VERSION 5.7 ;
  NOWIREEXTENSIONATPIN ON ;
  DIVIDERCHAR "/" ;
  BUSBITCHARS "[]" ;
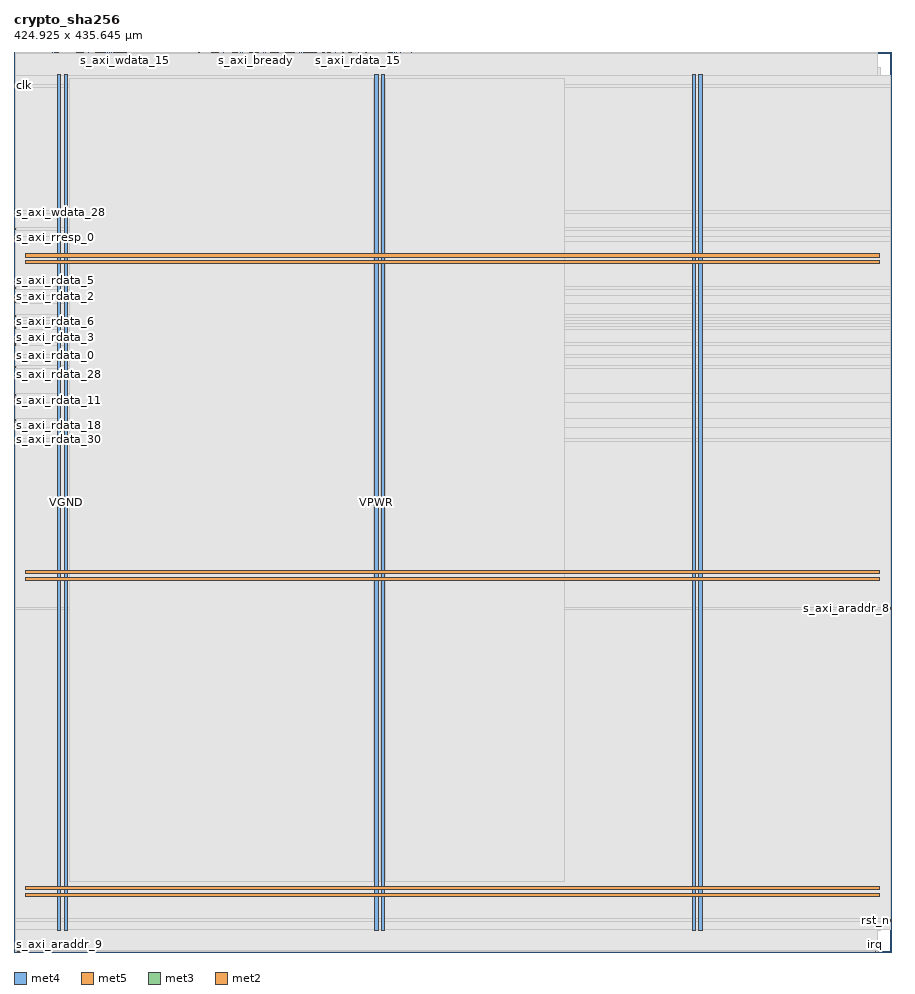
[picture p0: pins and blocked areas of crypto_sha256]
MACRO crypto_sha256
  CLASS BLOCK ;
  FOREIGN crypto_sha256 ;
  ORIGIN 0.000 0.000 ;
  SIZE 424.925 BY 435.645 ;
  PIN VGND
    DIRECTION INOUT ;
    USE GROUND ;
    PORT
      LAYER met4 ;
        RECT 24.340 10.640 25.940 424.560 ;
    END
    PORT
      LAYER met4 ;
        RECT 177.940 10.640 179.540 424.560 ;
    END
    PORT
      LAYER met4 ;
        RECT 331.540 10.640 333.140 424.560 ;
    END
    PORT
      LAYER met5 ;
        RECT 5.520 30.030 419.060 31.630 ;
    END
    PORT
      LAYER met5 ;
        RECT 5.520 183.210 419.060 184.810 ;
    END
    PORT
      LAYER met5 ;
        RECT 5.520 336.390 419.060 337.990 ;
    END
  END VGND
  PIN VPWR
    DIRECTION INOUT ;
    USE POWER ;
    PORT
      LAYER met4 ;
        RECT 21.040 10.640 22.640 424.560 ;
    END
    PORT
      LAYER met4 ;
        RECT 174.640 10.640 176.240 424.560 ;
    END
    PORT
      LAYER met4 ;
        RECT 328.240 10.640 329.840 424.560 ;
    END
    PORT
      LAYER met5 ;
        RECT 5.520 26.730 419.060 28.330 ;
    END
    PORT
      LAYER met5 ;
        RECT 5.520 179.910 419.060 181.510 ;
    END
    PORT
      LAYER met5 ;
        RECT 5.520 333.090 419.060 334.690 ;
    END
  END VPWR
  PIN clk
    DIRECTION INPUT ;
    USE SIGNAL ;
    ANTENNAGATEAREA 1.286700 ;
    ANTENNADIFFAREA 0.434700 ;
    PORT
      LAYER met3 ;
        RECT 0.000 418.920 0.600 419.520 ;
    END
  END clk
  PIN irq
    DIRECTION OUTPUT ;
    USE SIGNAL ;
    ANTENNAGATEAREA 0.434700 ;
    ANTENNADIFFAREA 1.137600 ;
    PORT
      LAYER met2 ;
        RECT 416.850 0.000 417.130 0.280 ;
    END
  END irq
  PIN rst_n
    DIRECTION INPUT ;
    USE SIGNAL ;
    ANTENNAGATEAREA 0.647700 ;
    ANTENNADIFFAREA 0.434700 ;
    PORT
      LAYER met3 ;
        RECT 424.325 15.000 424.925 15.600 ;
    END
  END rst_n
  PIN s_axi_araddr_0
    DIRECTION INPUT ;
    USE SIGNAL ;
    PORT
      LAYER met2 ;
        RECT 1.930 0.000 2.210 0.280 ;
    END
  END s_axi_araddr_0
  PIN s_axi_araddr_1
    DIRECTION INPUT ;
    USE SIGNAL ;
    PORT
      LAYER met2 ;
        RECT 2.850 0.000 3.130 0.280 ;
    END
  END s_axi_araddr_1
  PIN s_axi_araddr_10
    DIRECTION INPUT ;
    USE SIGNAL ;
    PORT
      LAYER met2 ;
        RECT 3.770 0.000 4.050 0.280 ;
    END
  END s_axi_araddr_10
  PIN s_axi_araddr_11
    DIRECTION INPUT ;
    USE SIGNAL ;
    ANTENNAGATEAREA 0.647700 ;
    ANTENNADIFFAREA 0.434700 ;
    PORT
      LAYER met2 ;
        RECT 192.370 435.365 192.650 435.645 ;
    END
  END s_axi_araddr_11
  PIN s_axi_araddr_2
    DIRECTION INPUT ;
    USE SIGNAL ;
    ANTENNAGATEAREA 0.647700 ;
    ANTENNADIFFAREA 0.434700 ;
    PORT
      LAYER met2 ;
        RECT 181.330 435.365 181.610 435.645 ;
    END
  END s_axi_araddr_2
  PIN s_axi_araddr_3
    DIRECTION INPUT ;
    USE SIGNAL ;
    ANTENNAGATEAREA 0.647700 ;
    ANTENNADIFFAREA 0.434700 ;
    PORT
      LAYER met2 ;
        RECT 185.010 435.365 185.290 435.645 ;
    END
  END s_axi_araddr_3
  PIN s_axi_araddr_4
    DIRECTION INPUT ;
    USE SIGNAL ;
    ANTENNAGATEAREA 0.647700 ;
    ANTENNADIFFAREA 0.434700 ;
    PORT
      LAYER met2 ;
        RECT 184.090 435.365 184.370 435.645 ;
    END
  END s_axi_araddr_4
  PIN s_axi_araddr_5
    DIRECTION INPUT ;
    USE SIGNAL ;
    ANTENNAGATEAREA 0.647700 ;
    ANTENNADIFFAREA 0.434700 ;
    PORT
      LAYER met2 ;
        RECT 183.170 435.365 183.450 435.645 ;
    END
  END s_axi_araddr_5
  PIN s_axi_araddr_6
    DIRECTION INPUT ;
    USE SIGNAL ;
    ANTENNAGATEAREA 0.647700 ;
    ANTENNADIFFAREA 0.434700 ;
    PORT
      LAYER met2 ;
        RECT 182.250 435.365 182.530 435.645 ;
    END
  END s_axi_araddr_6
  PIN s_axi_araddr_7
    DIRECTION INPUT ;
    USE SIGNAL ;
    ANTENNAGATEAREA 0.647700 ;
    ANTENNADIFFAREA 0.434700 ;
    PORT
      LAYER met2 ;
        RECT 186.850 435.365 187.130 435.645 ;
    END
  END s_axi_araddr_7
  PIN s_axi_araddr_8
    DIRECTION INPUT ;
    USE SIGNAL ;
    ANTENNAGATEAREA 0.631200 ;
    ANTENNADIFFAREA 0.434700 ;
    PORT
      LAYER met3 ;
        RECT 424.325 165.960 424.925 166.560 ;
    END
  END s_axi_araddr_8
  PIN s_axi_araddr_9
    DIRECTION INPUT ;
    USE SIGNAL ;
    PORT
      LAYER met2 ;
        RECT 4.690 0.000 4.970 0.280 ;
    END
  END s_axi_araddr_9
  PIN s_axi_arready
    DIRECTION OUTPUT ;
    USE SIGNAL ;
    ANTENNAGATEAREA 0.434700 ;
    ANTENNADIFFAREA 1.137600 ;
    PORT
      LAYER met2 ;
        RECT 127.970 435.365 128.250 435.645 ;
    END
  END s_axi_arready
  PIN s_axi_arvalid
    DIRECTION INPUT ;
    USE SIGNAL ;
    ANTENNAGATEAREA 0.647700 ;
    ANTENNADIFFAREA 0.434700 ;
    PORT
      LAYER met2 ;
        RECT 127.050 435.365 127.330 435.645 ;
    END
  END s_axi_arvalid
  PIN s_axi_awaddr_0
    DIRECTION INPUT ;
    USE SIGNAL ;
    ANTENNAGATEAREA 0.647700 ;
    ANTENNADIFFAREA 0.434700 ;
    PORT
      LAYER met2 ;
        RECT 132.570 435.365 132.850 435.645 ;
    END
  END s_axi_awaddr_0
  PIN s_axi_awaddr_1
    DIRECTION INPUT ;
    USE SIGNAL ;
    ANTENNAGATEAREA 0.647700 ;
    ANTENNADIFFAREA 0.434700 ;
    PORT
      LAYER met2 ;
        RECT 146.370 435.365 146.650 435.645 ;
    END
  END s_axi_awaddr_1
  PIN s_axi_awaddr_10
    DIRECTION INPUT ;
    USE SIGNAL ;
    ANTENNAGATEAREA 0.647700 ;
    ANTENNADIFFAREA 0.434700 ;
    PORT
      LAYER met2 ;
        RECT 141.770 435.365 142.050 435.645 ;
    END
  END s_axi_awaddr_10
  PIN s_axi_awaddr_11
    DIRECTION INPUT ;
    USE SIGNAL ;
    ANTENNAGATEAREA 0.647700 ;
    ANTENNADIFFAREA 0.434700 ;
    PORT
      LAYER met2 ;
        RECT 134.410 435.365 134.690 435.645 ;
    END
  END s_axi_awaddr_11
  PIN s_axi_awaddr_2
    DIRECTION INPUT ;
    USE SIGNAL ;
    ANTENNAGATEAREA 0.647700 ;
    ANTENNADIFFAREA 0.434700 ;
    PORT
      LAYER met2 ;
        RECT 115.090 435.365 115.370 435.645 ;
    END
  END s_axi_awaddr_2
  PIN s_axi_awaddr_3
    DIRECTION INPUT ;
    USE SIGNAL ;
    ANTENNAGATEAREA 0.647700 ;
    ANTENNADIFFAREA 0.434700 ;
    PORT
      LAYER met2 ;
        RECT 124.290 435.365 124.570 435.645 ;
    END
  END s_axi_awaddr_3
  PIN s_axi_awaddr_4
    DIRECTION INPUT ;
    USE SIGNAL ;
    ANTENNAGATEAREA 0.647700 ;
    ANTENNADIFFAREA 0.434700 ;
    PORT
      LAYER met2 ;
        RECT 139.930 435.365 140.210 435.645 ;
    END
  END s_axi_awaddr_4
  PIN s_axi_awaddr_5
    DIRECTION INPUT ;
    USE SIGNAL ;
    ANTENNAGATEAREA 0.647700 ;
    ANTENNADIFFAREA 0.434700 ;
    PORT
      LAYER met2 ;
        RECT 145.450 435.365 145.730 435.645 ;
    END
  END s_axi_awaddr_5
  PIN s_axi_awaddr_6
    DIRECTION INPUT ;
    USE SIGNAL ;
    ANTENNAGATEAREA 0.647700 ;
    ANTENNADIFFAREA 0.434700 ;
    PORT
      LAYER met2 ;
        RECT 144.530 435.365 144.810 435.645 ;
    END
  END s_axi_awaddr_6
  PIN s_axi_awaddr_7
    DIRECTION INPUT ;
    USE SIGNAL ;
    ANTENNAGATEAREA 0.647700 ;
    ANTENNADIFFAREA 0.434700 ;
    PORT
      LAYER met2 ;
        RECT 117.850 435.365 118.130 435.645 ;
    END
  END s_axi_awaddr_7
  PIN s_axi_awaddr_8
    DIRECTION INPUT ;
    USE SIGNAL ;
    ANTENNAGATEAREA 0.647700 ;
    ANTENNADIFFAREA 0.434700 ;
    PORT
      LAYER met2 ;
        RECT 135.330 435.365 135.610 435.645 ;
    END
  END s_axi_awaddr_8
  PIN s_axi_awaddr_9
    DIRECTION INPUT ;
    USE SIGNAL ;
    ANTENNAGATEAREA 0.647700 ;
    ANTENNADIFFAREA 0.434700 ;
    PORT
      LAYER met2 ;
        RECT 126.130 435.365 126.410 435.645 ;
    END
  END s_axi_awaddr_9
  PIN s_axi_awready
    DIRECTION OUTPUT ;
    USE SIGNAL ;
    ANTENNAGATEAREA 0.434700 ;
    ANTENNADIFFAREA 1.137600 ;
    PORT
      LAYER met2 ;
        RECT 125.210 435.365 125.490 435.645 ;
    END
  END s_axi_awready
  PIN s_axi_awvalid
    DIRECTION INPUT ;
    USE SIGNAL ;
    ANTENNAGATEAREA 0.647700 ;
    ANTENNADIFFAREA 0.434700 ;
    PORT
      LAYER met2 ;
        RECT 121.530 435.365 121.810 435.645 ;
    END
  END s_axi_awvalid
  PIN s_axi_bready
    DIRECTION INPUT ;
    USE SIGNAL ;
    ANTENNAGATEAREA 0.647700 ;
    ANTENNADIFFAREA 0.434700 ;
    PORT
      LAYER met2 ;
        RECT 116.930 435.365 117.210 435.645 ;
    END
  END s_axi_bready
  PIN s_axi_bresp_0
    DIRECTION OUTPUT ;
    USE SIGNAL ;
    ANTENNAGATEAREA 0.434700 ;
    ANTENNADIFFAREA 1.137600 ;
    PORT
      LAYER met2 ;
        RECT 110.490 435.365 110.770 435.645 ;
    END
  END s_axi_bresp_0
  PIN s_axi_bresp_1
    DIRECTION OUTPUT ;
    USE SIGNAL ;
    ANTENNAGATEAREA 0.434700 ;
    ANTENNADIFFAREA 1.137600 ;
    PORT
      LAYER met2 ;
        RECT 109.570 435.365 109.850 435.645 ;
    END
  END s_axi_bresp_1
  PIN s_axi_bvalid
    DIRECTION OUTPUT ;
    USE SIGNAL ;
    ANTENNAGATEAREA 0.434700 ;
    ANTENNADIFFAREA 1.137600 ;
    PORT
      LAYER met2 ;
        RECT 120.610 435.365 120.890 435.645 ;
    END
  END s_axi_bvalid
  PIN s_axi_rdata_0
    DIRECTION OUTPUT ;
    USE SIGNAL ;
    ANTENNAGATEAREA 0.434700 ;
    ANTENNADIFFAREA 1.137600 ;
    PORT
      LAYER met3 ;
        RECT 0.000 288.360 0.600 288.960 ;
    END
  END s_axi_rdata_0
  PIN s_axi_rdata_1
    DIRECTION OUTPUT ;
    USE SIGNAL ;
    ANTENNAGATEAREA 0.434700 ;
    ANTENNADIFFAREA 1.137600 ;
    PORT
      LAYER met3 ;
        RECT 0.000 301.960 0.600 302.560 ;
    END
  END s_axi_rdata_1
  PIN s_axi_rdata_10
    DIRECTION OUTPUT ;
    USE SIGNAL ;
    ANTENNAGATEAREA 0.434700 ;
    ANTENNADIFFAREA 1.137600 ;
    PORT
      LAYER met2 ;
        RECT 131.650 435.365 131.930 435.645 ;
    END
  END s_axi_rdata_10
  PIN s_axi_rdata_11
    DIRECTION OUTPUT ;
    USE SIGNAL ;
    ANTENNAGATEAREA 0.434700 ;
    ANTENNADIFFAREA 1.137600 ;
    PORT
      LAYER met3 ;
        RECT 0.000 266.600 0.600 267.200 ;
    END
  END s_axi_rdata_11
  PIN s_axi_rdata_12
    DIRECTION OUTPUT ;
    USE SIGNAL ;
    ANTENNAGATEAREA 0.434700 ;
    ANTENNADIFFAREA 1.137600 ;
    PORT
      LAYER met3 ;
        RECT 0.000 257.080 0.600 257.680 ;
    END
  END s_axi_rdata_12
  PIN s_axi_rdata_13
    DIRECTION OUTPUT ;
    USE SIGNAL ;
    ANTENNAGATEAREA 0.434700 ;
    ANTENNADIFFAREA 1.137600 ;
    PORT
      LAYER met2 ;
        RECT 152.810 435.365 153.090 435.645 ;
    END
  END s_axi_rdata_13
  PIN s_axi_rdata_14
    DIRECTION OUTPUT ;
    USE SIGNAL ;
    ANTENNAGATEAREA 0.434700 ;
    ANTENNADIFFAREA 1.137600 ;
    PORT
      LAYER met2 ;
        RECT 155.570 435.365 155.850 435.645 ;
    END
  END s_axi_rdata_14
  PIN s_axi_rdata_15
    DIRECTION OUTPUT ;
    USE SIGNAL ;
    ANTENNAGATEAREA 0.434700 ;
    ANTENNADIFFAREA 1.137600 ;
    PORT
      LAYER met2 ;
        RECT 166.610 435.365 166.890 435.645 ;
    END
  END s_axi_rdata_15
  PIN s_axi_rdata_16
    DIRECTION OUTPUT ;
    USE SIGNAL ;
    ANTENNAGATEAREA 0.434700 ;
    ANTENNADIFFAREA 1.137600 ;
    PORT
      LAYER met2 ;
        RECT 142.690 435.365 142.970 435.645 ;
    END
  END s_axi_rdata_16
  PIN s_axi_rdata_17
    DIRECTION OUTPUT ;
    USE SIGNAL ;
    ANTENNAGATEAREA 0.434700 ;
    ANTENNADIFFAREA 1.137600 ;
    PORT
      LAYER met2 ;
        RECT 140.850 435.365 141.130 435.645 ;
    END
  END s_axi_rdata_17
  PIN s_axi_rdata_18
    DIRECTION OUTPUT ;
    USE SIGNAL ;
    ANTENNAGATEAREA 0.434700 ;
    ANTENNADIFFAREA 1.137600 ;
    PORT
      LAYER met3 ;
        RECT 0.000 254.360 0.600 254.960 ;
    END
  END s_axi_rdata_18
  PIN s_axi_rdata_19
    DIRECTION OUTPUT ;
    USE SIGNAL ;
    ANTENNAGATEAREA 0.434700 ;
    ANTENNADIFFAREA 1.137600 ;
    PORT
      LAYER met3 ;
        RECT 0.000 255.720 0.600 256.320 ;
    END
  END s_axi_rdata_19
  PIN s_axi_rdata_2
    DIRECTION OUTPUT ;
    USE SIGNAL ;
    ANTENNAGATEAREA 0.434700 ;
    ANTENNADIFFAREA 1.137600 ;
    PORT
      LAYER met3 ;
        RECT 0.000 316.920 0.600 317.520 ;
    END
  END s_axi_rdata_2
  PIN s_axi_rdata_20
    DIRECTION OUTPUT ;
    USE SIGNAL ;
    ANTENNAGATEAREA 0.434700 ;
    ANTENNADIFFAREA 1.137600 ;
    PORT
      LAYER met2 ;
        RECT 159.250 435.365 159.530 435.645 ;
    END
  END s_axi_rdata_20
  PIN s_axi_rdata_21
    DIRECTION OUTPUT ;
    USE SIGNAL ;
    ANTENNAGATEAREA 0.434700 ;
    ANTENNADIFFAREA 1.137600 ;
    PORT
      LAYER met2 ;
        RECT 162.930 435.365 163.210 435.645 ;
    END
  END s_axi_rdata_21
  PIN s_axi_rdata_22
    DIRECTION OUTPUT ;
    USE SIGNAL ;
    ANTENNAGATEAREA 0.434700 ;
    ANTENNADIFFAREA 1.137600 ;
    PORT
      LAYER met3 ;
        RECT 0.000 267.960 0.600 268.560 ;
    END
  END s_axi_rdata_22
  PIN s_axi_rdata_23
    DIRECTION OUTPUT ;
    USE SIGNAL ;
    ANTENNAGATEAREA 0.434700 ;
    ANTENNADIFFAREA 1.137600 ;
    PORT
      LAYER met2 ;
        RECT 162.010 435.365 162.290 435.645 ;
    END
  END s_axi_rdata_23
  PIN s_axi_rdata_24
    DIRECTION OUTPUT ;
    USE SIGNAL ;
    ANTENNAGATEAREA 0.434700 ;
    ANTENNADIFFAREA 1.137600 ;
    PORT
      LAYER met2 ;
        RECT 170.290 435.365 170.570 435.645 ;
    END
  END s_axi_rdata_24
  PIN s_axi_rdata_25
    DIRECTION OUTPUT ;
    USE SIGNAL ;
    ANTENNAGATEAREA 0.434700 ;
    ANTENNADIFFAREA 1.137600 ;
    PORT
      LAYER met2 ;
        RECT 150.050 435.365 150.330 435.645 ;
    END
  END s_axi_rdata_25
  PIN s_axi_rdata_26
    DIRECTION OUTPUT ;
    USE SIGNAL ;
    ANTENNAGATEAREA 0.434700 ;
    ANTENNADIFFAREA 1.137600 ;
    PORT
      LAYER met2 ;
        RECT 143.610 435.365 143.890 435.645 ;
    END
  END s_axi_rdata_26
  PIN s_axi_rdata_27
    DIRECTION OUTPUT ;
    USE SIGNAL ;
    ANTENNAGATEAREA 0.434700 ;
    ANTENNADIFFAREA 1.137600 ;
    PORT
      LAYER met2 ;
        RECT 151.890 435.365 152.170 435.645 ;
    END
  END s_axi_rdata_27
  PIN s_axi_rdata_28
    DIRECTION OUTPUT ;
    USE SIGNAL ;
    ANTENNAGATEAREA 0.434700 ;
    ANTENNADIFFAREA 1.137600 ;
    PORT
      LAYER met3 ;
        RECT 0.000 282.920 0.600 283.520 ;
    END
  END s_axi_rdata_28
  PIN s_axi_rdata_29
    DIRECTION OUTPUT ;
    USE SIGNAL ;
    ANTENNAGATEAREA 0.434700 ;
    ANTENNADIFFAREA 1.137600 ;
    PORT
      LAYER met3 ;
        RECT 0.000 269.320 0.600 269.920 ;
    END
  END s_axi_rdata_29
  PIN s_axi_rdata_3
    DIRECTION OUTPUT ;
    USE SIGNAL ;
    ANTENNAGATEAREA 0.434700 ;
    ANTENNADIFFAREA 1.137600 ;
    PORT
      LAYER met3 ;
        RECT 0.000 293.800 0.600 294.400 ;
    END
  END s_axi_rdata_3
  PIN s_axi_rdata_30
    DIRECTION OUTPUT ;
    USE SIGNAL ;
    ANTENNAGATEAREA 0.434700 ;
    ANTENNADIFFAREA 1.137600 ;
    PORT
      LAYER met3 ;
        RECT 0.000 247.560 0.600 248.160 ;
    END
  END s_axi_rdata_30
  PIN s_axi_rdata_31
    DIRECTION OUTPUT ;
    USE SIGNAL ;
    ANTENNAGATEAREA 0.434700 ;
    ANTENNADIFFAREA 1.137600 ;
    PORT
      LAYER met2 ;
        RECT 149.130 435.365 149.410 435.645 ;
    END
  END s_axi_rdata_31
  PIN s_axi_rdata_4
    DIRECTION OUTPUT ;
    USE SIGNAL ;
    ANTENNAGATEAREA 0.434700 ;
    ANTENNADIFFAREA 1.137600 ;
    PORT
      LAYER met3 ;
        RECT 0.000 314.200 0.600 314.800 ;
    END
  END s_axi_rdata_4
  PIN s_axi_rdata_5
    DIRECTION OUTPUT ;
    USE SIGNAL ;
    ANTENNAGATEAREA 0.434700 ;
    ANTENNADIFFAREA 1.137600 ;
    PORT
      LAYER met3 ;
        RECT 0.000 321.000 0.600 321.600 ;
    END
  END s_axi_rdata_5
  PIN s_axi_rdata_6
    DIRECTION OUTPUT ;
    USE SIGNAL ;
    ANTENNAGATEAREA 0.434700 ;
    ANTENNADIFFAREA 1.137600 ;
    PORT
      LAYER met3 ;
        RECT 0.000 304.680 0.600 305.280 ;
    END
  END s_axi_rdata_6
  PIN s_axi_rdata_7
    DIRECTION OUTPUT ;
    USE SIGNAL ;
    ANTENNAGATEAREA 0.434700 ;
    ANTENNADIFFAREA 1.137600 ;
    PORT
      LAYER met3 ;
        RECT 0.000 307.400 0.600 308.000 ;
    END
  END s_axi_rdata_7
  PIN s_axi_rdata_8
    DIRECTION OUTPUT ;
    USE SIGNAL ;
    ANTENNAGATEAREA 0.434700 ;
    ANTENNADIFFAREA 1.137600 ;
    PORT
      LAYER met2 ;
        RECT 138.090 435.365 138.370 435.645 ;
    END
  END s_axi_rdata_8
  PIN s_axi_rdata_9
    DIRECTION OUTPUT ;
    USE SIGNAL ;
    ANTENNAGATEAREA 0.434700 ;
    ANTENNADIFFAREA 1.137600 ;
    PORT
      LAYER met3 ;
        RECT 0.000 315.560 0.600 316.160 ;
    END
  END s_axi_rdata_9
  PIN s_axi_rready
    DIRECTION INPUT ;
    USE SIGNAL ;
    ANTENNAGATEAREA 0.647700 ;
    ANTENNADIFFAREA 0.434700 ;
    PORT
      LAYER met2 ;
        RECT 133.490 435.365 133.770 435.645 ;
    END
  END s_axi_rready
  PIN s_axi_rresp_0
    DIRECTION OUTPUT ;
    USE SIGNAL ;
    ANTENNAGATEAREA 0.434700 ;
    ANTENNADIFFAREA 1.137600 ;
    PORT
      LAYER met3 ;
        RECT 0.000 345.480 0.600 346.080 ;
    END
  END s_axi_rresp_0
  PIN s_axi_rresp_1
    DIRECTION OUTPUT ;
    USE SIGNAL ;
    ANTENNAGATEAREA 0.434700 ;
    ANTENNADIFFAREA 1.137600 ;
    PORT
      LAYER met3 ;
        RECT 0.000 344.120 0.600 344.720 ;
    END
  END s_axi_rresp_1
  PIN s_axi_rvalid
    DIRECTION OUTPUT ;
    USE SIGNAL ;
    ANTENNAGATEAREA 0.434700 ;
    ANTENNADIFFAREA 1.137600 ;
    PORT
      LAYER met2 ;
        RECT 139.010 435.365 139.290 435.645 ;
    END
  END s_axi_rvalid
  PIN s_axi_wdata_0
    DIRECTION INPUT ;
    USE SIGNAL ;
    ANTENNAGATEAREA 0.647700 ;
    ANTENNADIFFAREA 0.434700 ;
    PORT
      LAYER met2 ;
        RECT 96.690 435.365 96.970 435.645 ;
    END
  END s_axi_wdata_0
  PIN s_axi_wdata_1
    DIRECTION INPUT ;
    USE SIGNAL ;
    ANTENNAGATEAREA 0.647700 ;
    ANTENNADIFFAREA 0.434700 ;
    PORT
      LAYER met2 ;
        RECT 106.810 435.365 107.090 435.645 ;
    END
  END s_axi_wdata_1
  PIN s_axi_wdata_10
    DIRECTION INPUT ;
    USE SIGNAL ;
    ANTENNAGATEAREA 0.647700 ;
    ANTENNADIFFAREA 0.434700 ;
    PORT
      LAYER met2 ;
        RECT 95.770 435.365 96.050 435.645 ;
    END
  END s_axi_wdata_10
  PIN s_axi_wdata_11
    DIRECTION INPUT ;
    USE SIGNAL ;
    ANTENNAGATEAREA 0.647700 ;
    ANTENNADIFFAREA 0.434700 ;
    PORT
      LAYER met2 ;
        RECT 39.650 435.365 39.930 435.645 ;
    END
  END s_axi_wdata_11
  PIN s_axi_wdata_12
    DIRECTION INPUT ;
    USE SIGNAL ;
    ANTENNAGATEAREA 0.647700 ;
    ANTENNADIFFAREA 0.434700 ;
    PORT
      LAYER met2 ;
        RECT 50.690 435.365 50.970 435.645 ;
    END
  END s_axi_wdata_12
  PIN s_axi_wdata_13
    DIRECTION INPUT ;
    USE SIGNAL ;
    ANTENNAGATEAREA 0.647700 ;
    ANTENNADIFFAREA 0.434700 ;
    PORT
      LAYER met2 ;
        RECT 101.290 435.365 101.570 435.645 ;
    END
  END s_axi_wdata_13
  PIN s_axi_wdata_14
    DIRECTION INPUT ;
    USE SIGNAL ;
    ANTENNAGATEAREA 0.647700 ;
    ANTENNADIFFAREA 0.434700 ;
    PORT
      LAYER met2 ;
        RECT 40.570 435.365 40.850 435.645 ;
    END
  END s_axi_wdata_14
  PIN s_axi_wdata_15
    DIRECTION INPUT ;
    USE SIGNAL ;
    ANTENNAGATEAREA 0.647700 ;
    ANTENNADIFFAREA 0.434700 ;
    PORT
      LAYER met2 ;
        RECT 53.450 435.365 53.730 435.645 ;
    END
  END s_axi_wdata_15
  PIN s_axi_wdata_16
    DIRECTION INPUT ;
    USE SIGNAL ;
    ANTENNAGATEAREA 0.647700 ;
    ANTENNADIFFAREA 0.434700 ;
    PORT
      LAYER met2 ;
        RECT 49.770 435.365 50.050 435.645 ;
    END
  END s_axi_wdata_16
  PIN s_axi_wdata_17
    DIRECTION INPUT ;
    USE SIGNAL ;
    ANTENNAGATEAREA 0.647700 ;
    ANTENNADIFFAREA 0.434700 ;
    PORT
      LAYER met2 ;
        RECT 41.490 435.365 41.770 435.645 ;
    END
  END s_axi_wdata_17
  PIN s_axi_wdata_18
    DIRECTION INPUT ;
    USE SIGNAL ;
    ANTENNAGATEAREA 0.647700 ;
    ANTENNADIFFAREA 0.434700 ;
    PORT
      LAYER met2 ;
        RECT 47.010 435.365 47.290 435.645 ;
    END
  END s_axi_wdata_18
  PIN s_axi_wdata_19
    DIRECTION INPUT ;
    USE SIGNAL ;
    ANTENNAGATEAREA 0.647700 ;
    ANTENNADIFFAREA 0.434700 ;
    PORT
      LAYER met2 ;
        RECT 51.610 435.365 51.890 435.645 ;
    END
  END s_axi_wdata_19
  PIN s_axi_wdata_2
    DIRECTION INPUT ;
    USE SIGNAL ;
    ANTENNAGATEAREA 0.647700 ;
    ANTENNADIFFAREA 0.434700 ;
    PORT
      LAYER met2 ;
        RECT 54.370 435.365 54.650 435.645 ;
    END
  END s_axi_wdata_2
  PIN s_axi_wdata_20
    DIRECTION INPUT ;
    USE SIGNAL ;
    ANTENNAGATEAREA 0.647700 ;
    ANTENNADIFFAREA 0.434700 ;
    PORT
      LAYER met2 ;
        RECT 42.410 435.365 42.690 435.645 ;
    END
  END s_axi_wdata_20
  PIN s_axi_wdata_21
    DIRECTION INPUT ;
    USE SIGNAL ;
    ANTENNAGATEAREA 0.647700 ;
    ANTENNADIFFAREA 0.434700 ;
    PORT
      LAYER met2 ;
        RECT 20.330 435.365 20.610 435.645 ;
    END
  END s_axi_wdata_21
  PIN s_axi_wdata_22
    DIRECTION INPUT ;
    USE SIGNAL ;
    ANTENNAGATEAREA 0.647700 ;
    ANTENNADIFFAREA 0.434700 ;
    PORT
      LAYER met2 ;
        RECT 46.090 435.365 46.370 435.645 ;
    END
  END s_axi_wdata_22
  PIN s_axi_wdata_23
    DIRECTION INPUT ;
    USE SIGNAL ;
    ANTENNAGATEAREA 0.647700 ;
    ANTENNADIFFAREA 0.434700 ;
    PORT
      LAYER met2 ;
        RECT 18.490 435.365 18.770 435.645 ;
    END
  END s_axi_wdata_23
  PIN s_axi_wdata_24
    DIRECTION INPUT ;
    USE SIGNAL ;
    ANTENNAGATEAREA 0.647700 ;
    ANTENNADIFFAREA 0.434700 ;
    PORT
      LAYER met2 ;
        RECT 30.450 435.365 30.730 435.645 ;
    END
  END s_axi_wdata_24
  PIN s_axi_wdata_25
    DIRECTION INPUT ;
    USE SIGNAL ;
    ANTENNAGATEAREA 0.647700 ;
    ANTENNADIFFAREA 0.434700 ;
    PORT
      LAYER met2 ;
        RECT 19.410 435.365 19.690 435.645 ;
    END
  END s_axi_wdata_25
  PIN s_axi_wdata_26
    DIRECTION INPUT ;
    USE SIGNAL ;
    ANTENNAGATEAREA 0.647700 ;
    ANTENNADIFFAREA 0.434700 ;
    PORT
      LAYER met2 ;
        RECT 21.250 435.365 21.530 435.645 ;
    END
  END s_axi_wdata_26
  PIN s_axi_wdata_27
    DIRECTION INPUT ;
    USE SIGNAL ;
    ANTENNAGATEAREA 0.647700 ;
    ANTENNADIFFAREA 0.434700 ;
    PORT
      LAYER met2 ;
        RECT 31.370 435.365 31.650 435.645 ;
    END
  END s_axi_wdata_27
  PIN s_axi_wdata_28
    DIRECTION INPUT ;
    USE SIGNAL ;
    ANTENNAGATEAREA 0.647700 ;
    ANTENNADIFFAREA 0.434700 ;
    PORT
      LAYER met3 ;
        RECT 0.000 357.720 0.600 358.320 ;
    END
  END s_axi_wdata_28
  PIN s_axi_wdata_29
    DIRECTION INPUT ;
    USE SIGNAL ;
    ANTENNAGATEAREA 0.647700 ;
    ANTENNADIFFAREA 0.434700 ;
    PORT
      LAYER met2 ;
        RECT 33.210 435.365 33.490 435.645 ;
    END
  END s_axi_wdata_29
  PIN s_axi_wdata_3
    DIRECTION INPUT ;
    USE SIGNAL ;
    ANTENNAGATEAREA 0.647700 ;
    ANTENNADIFFAREA 0.434700 ;
    PORT
      LAYER met2 ;
        RECT 114.170 435.365 114.450 435.645 ;
    END
  END s_axi_wdata_3
  PIN s_axi_wdata_30
    DIRECTION INPUT ;
    USE SIGNAL ;
    ANTENNAGATEAREA 0.647700 ;
    ANTENNADIFFAREA 0.434700 ;
    PORT
      LAYER met2 ;
        RECT 52.530 435.365 52.810 435.645 ;
    END
  END s_axi_wdata_30
  PIN s_axi_wdata_31
    DIRECTION INPUT ;
    USE SIGNAL ;
    ANTENNAGATEAREA 0.647700 ;
    ANTENNADIFFAREA 0.434700 ;
    PORT
      LAYER met3 ;
        RECT 0.000 349.560 0.600 350.160 ;
    END
  END s_axi_wdata_31
  PIN s_axi_wdata_4
    DIRECTION INPUT ;
    USE SIGNAL ;
    ANTENNAGATEAREA 0.647700 ;
    ANTENNADIFFAREA 0.434700 ;
    PORT
      LAYER met2 ;
        RECT 98.530 435.365 98.810 435.645 ;
    END
  END s_axi_wdata_4
  PIN s_axi_wdata_5
    DIRECTION INPUT ;
    USE SIGNAL ;
    ANTENNAGATEAREA 0.647700 ;
    ANTENNADIFFAREA 0.434700 ;
    PORT
      LAYER met2 ;
        RECT 47.930 435.365 48.210 435.645 ;
    END
  END s_axi_wdata_5
  PIN s_axi_wdata_6
    DIRECTION INPUT ;
    USE SIGNAL ;
    ANTENNAGATEAREA 0.647700 ;
    ANTENNADIFFAREA 0.434700 ;
    PORT
      LAYER met2 ;
        RECT 45.170 435.365 45.450 435.645 ;
    END
  END s_axi_wdata_6
  PIN s_axi_wdata_7
    DIRECTION INPUT ;
    USE SIGNAL ;
    ANTENNAGATEAREA 0.647700 ;
    ANTENNADIFFAREA 0.434700 ;
    PORT
      LAYER met2 ;
        RECT 44.250 435.365 44.530 435.645 ;
    END
  END s_axi_wdata_7
  PIN s_axi_wdata_8
    DIRECTION INPUT ;
    USE SIGNAL ;
    ANTENNAGATEAREA 0.647700 ;
    ANTENNADIFFAREA 0.434700 ;
    PORT
      LAYER met2 ;
        RECT 89.330 435.365 89.610 435.645 ;
    END
  END s_axi_wdata_8
  PIN s_axi_wdata_9
    DIRECTION INPUT ;
    USE SIGNAL ;
    ANTENNAGATEAREA 0.647700 ;
    ANTENNADIFFAREA 0.434700 ;
    PORT
      LAYER met2 ;
        RECT 97.610 435.365 97.890 435.645 ;
    END
  END s_axi_wdata_9
  PIN s_axi_wready
    DIRECTION OUTPUT ;
    USE SIGNAL ;
    ANTENNAGATEAREA 0.434700 ;
    ANTENNADIFFAREA 1.137600 ;
    PORT
      LAYER met2 ;
        RECT 107.730 435.365 108.010 435.645 ;
    END
  END s_axi_wready
  PIN s_axi_wstrb_0
    DIRECTION INPUT ;
    USE SIGNAL ;
    ANTENNAGATEAREA 0.647700 ;
    ANTENNADIFFAREA 0.434700 ;
    PORT
      LAYER met2 ;
        RECT 48.850 435.365 49.130 435.645 ;
    END
  END s_axi_wstrb_0
  PIN s_axi_wstrb_1
    DIRECTION INPUT ;
    USE SIGNAL ;
    ANTENNAGATEAREA 0.647700 ;
    ANTENNADIFFAREA 0.434700 ;
    PORT
      LAYER met2 ;
        RECT 43.330 435.365 43.610 435.645 ;
    END
  END s_axi_wstrb_1
  PIN s_axi_wstrb_2
    DIRECTION INPUT ;
    USE SIGNAL ;
    ANTENNAGATEAREA 0.647700 ;
    ANTENNADIFFAREA 0.434700 ;
    PORT
      LAYER met2 ;
        RECT 32.290 435.365 32.570 435.645 ;
    END
  END s_axi_wstrb_2
  PIN s_axi_wstrb_3
    DIRECTION INPUT ;
    USE SIGNAL ;
    ANTENNAGATEAREA 0.647700 ;
    ANTENNADIFFAREA 0.434700 ;
    PORT
      LAYER met2 ;
        RECT 35.970 435.365 36.250 435.645 ;
    END
  END s_axi_wstrb_3
  PIN s_axi_wvalid
    DIRECTION INPUT ;
    USE SIGNAL ;
    ANTENNAGATEAREA 0.647700 ;
    ANTENNADIFFAREA 0.434700 ;
    PORT
      LAYER met2 ;
        RECT 105.890 435.365 106.170 435.645 ;
    END
  END s_axi_wvalid
  OBS
      LAYER nwell ;
        RECT 5.330 10.795 419.250 424.405 ;
      LAYER li1 ;
        RECT 5.520 10.795 419.060 424.405 ;
      LAYER met1 ;
        RECT 0.530 10.640 419.360 428.360 ;
      LAYER met2 ;
        RECT 0.550 435.085 18.210 435.365 ;
        RECT 19.050 435.085 19.130 435.365 ;
        RECT 19.970 435.085 20.050 435.365 ;
        RECT 20.890 435.085 20.970 435.365 ;
        RECT 21.810 435.085 30.170 435.365 ;
        RECT 31.010 435.085 31.090 435.365 ;
        RECT 31.930 435.085 32.010 435.365 ;
        RECT 32.850 435.085 32.930 435.365 ;
        RECT 33.770 435.085 35.690 435.365 ;
        RECT 36.530 435.085 39.370 435.365 ;
        RECT 40.210 435.085 40.290 435.365 ;
        RECT 41.130 435.085 41.210 435.365 ;
        RECT 42.050 435.085 42.130 435.365 ;
        RECT 42.970 435.085 43.050 435.365 ;
        RECT 43.890 435.085 43.970 435.365 ;
        RECT 44.810 435.085 44.890 435.365 ;
        RECT 45.730 435.085 45.810 435.365 ;
        RECT 46.650 435.085 46.730 435.365 ;
        RECT 47.570 435.085 47.650 435.365 ;
        RECT 48.490 435.085 48.570 435.365 ;
        RECT 49.410 435.085 49.490 435.365 ;
        RECT 50.330 435.085 50.410 435.365 ;
        RECT 51.250 435.085 51.330 435.365 ;
        RECT 52.170 435.085 52.250 435.365 ;
        RECT 53.090 435.085 53.170 435.365 ;
        RECT 54.010 435.085 54.090 435.365 ;
        RECT 54.930 435.085 89.050 435.365 ;
        RECT 89.890 435.085 95.490 435.365 ;
        RECT 96.330 435.085 96.410 435.365 ;
        RECT 97.250 435.085 97.330 435.365 ;
        RECT 98.170 435.085 98.250 435.365 ;
        RECT 99.090 435.085 101.010 435.365 ;
        RECT 101.850 435.085 105.610 435.365 ;
        RECT 106.450 435.085 106.530 435.365 ;
        RECT 107.370 435.085 107.450 435.365 ;
        RECT 108.290 435.085 109.290 435.365 ;
        RECT 110.130 435.085 110.210 435.365 ;
        RECT 111.050 435.085 113.890 435.365 ;
        RECT 114.730 435.085 114.810 435.365 ;
        RECT 115.650 435.085 116.650 435.365 ;
        RECT 117.490 435.085 117.570 435.365 ;
        RECT 118.410 435.085 120.330 435.365 ;
        RECT 121.170 435.085 121.250 435.365 ;
        RECT 122.090 435.085 124.010 435.365 ;
        RECT 124.850 435.085 124.930 435.365 ;
        RECT 125.770 435.085 125.850 435.365 ;
        RECT 126.690 435.085 126.770 435.365 ;
        RECT 127.610 435.085 127.690 435.365 ;
        RECT 128.530 435.085 131.370 435.365 ;
        RECT 132.210 435.085 132.290 435.365 ;
        RECT 133.130 435.085 133.210 435.365 ;
        RECT 134.050 435.085 134.130 435.365 ;
        RECT 134.970 435.085 135.050 435.365 ;
        RECT 135.890 435.085 137.810 435.365 ;
        RECT 138.650 435.085 138.730 435.365 ;
        RECT 139.570 435.085 139.650 435.365 ;
        RECT 140.490 435.085 140.570 435.365 ;
        RECT 141.410 435.085 141.490 435.365 ;
        RECT 142.330 435.085 142.410 435.365 ;
        RECT 143.250 435.085 143.330 435.365 ;
        RECT 144.170 435.085 144.250 435.365 ;
        RECT 145.090 435.085 145.170 435.365 ;
        RECT 146.010 435.085 146.090 435.365 ;
        RECT 146.930 435.085 148.850 435.365 ;
        RECT 149.690 435.085 149.770 435.365 ;
        RECT 150.610 435.085 151.610 435.365 ;
        RECT 152.450 435.085 152.530 435.365 ;
        RECT 153.370 435.085 155.290 435.365 ;
        RECT 156.130 435.085 158.970 435.365 ;
        RECT 159.810 435.085 161.730 435.365 ;
        RECT 162.570 435.085 162.650 435.365 ;
        RECT 163.490 435.085 166.330 435.365 ;
        RECT 167.170 435.085 170.010 435.365 ;
        RECT 170.850 435.085 181.050 435.365 ;
        RECT 181.890 435.085 181.970 435.365 ;
        RECT 182.810 435.085 182.890 435.365 ;
        RECT 183.730 435.085 183.810 435.365 ;
        RECT 184.650 435.085 184.730 435.365 ;
        RECT 185.570 435.085 186.570 435.365 ;
        RECT 187.410 435.085 192.090 435.365 ;
        RECT 192.930 435.085 418.040 435.365 ;
        RECT 0.550 0.560 418.040 435.085 ;
        RECT 0.550 0.280 1.650 0.560 ;
        RECT 2.490 0.280 2.570 0.560 ;
        RECT 3.410 0.280 3.490 0.560 ;
        RECT 4.330 0.280 4.410 0.560 ;
        RECT 5.250 0.280 416.570 0.560 ;
        RECT 417.410 0.280 418.040 0.560 ;
      LAYER met3 ;
        RECT 0.600 419.920 424.325 424.485 ;
        RECT 1.000 418.520 424.325 419.920 ;
        RECT 0.600 358.720 424.325 418.520 ;
        RECT 1.000 357.320 424.325 358.720 ;
        RECT 0.600 350.560 424.325 357.320 ;
        RECT 1.000 349.160 424.325 350.560 ;
        RECT 0.600 346.480 424.325 349.160 ;
        RECT 1.000 343.720 424.325 346.480 ;
        RECT 0.600 322.000 424.325 343.720 ;
        RECT 1.000 320.600 424.325 322.000 ;
        RECT 0.600 317.920 424.325 320.600 ;
        RECT 1.000 313.800 424.325 317.920 ;
        RECT 0.600 308.400 424.325 313.800 ;
        RECT 1.000 307.000 424.325 308.400 ;
        RECT 0.600 305.680 424.325 307.000 ;
        RECT 1.000 304.280 424.325 305.680 ;
        RECT 0.600 302.960 424.325 304.280 ;
        RECT 1.000 301.560 424.325 302.960 ;
        RECT 0.600 294.800 424.325 301.560 ;
        RECT 1.000 293.400 424.325 294.800 ;
        RECT 0.600 289.360 424.325 293.400 ;
        RECT 1.000 287.960 424.325 289.360 ;
        RECT 0.600 283.920 424.325 287.960 ;
        RECT 1.000 282.520 424.325 283.920 ;
        RECT 0.600 270.320 424.325 282.520 ;
        RECT 1.000 266.200 424.325 270.320 ;
        RECT 0.600 258.080 424.325 266.200 ;
        RECT 1.000 253.960 424.325 258.080 ;
        RECT 0.600 248.560 424.325 253.960 ;
        RECT 1.000 247.160 424.325 248.560 ;
        RECT 0.600 166.960 424.325 247.160 ;
        RECT 0.600 165.560 423.925 166.960 ;
        RECT 0.600 16.000 424.325 165.560 ;
        RECT 0.600 14.600 423.925 16.000 ;
        RECT 0.600 10.715 424.325 14.600 ;
      LAYER met4 ;
        RECT 26.975 34.175 174.240 422.785 ;
        RECT 176.640 34.175 177.540 422.785 ;
        RECT 179.940 34.175 266.505 422.785 ;
  END
END crypto_sha256
END LIBRARY

